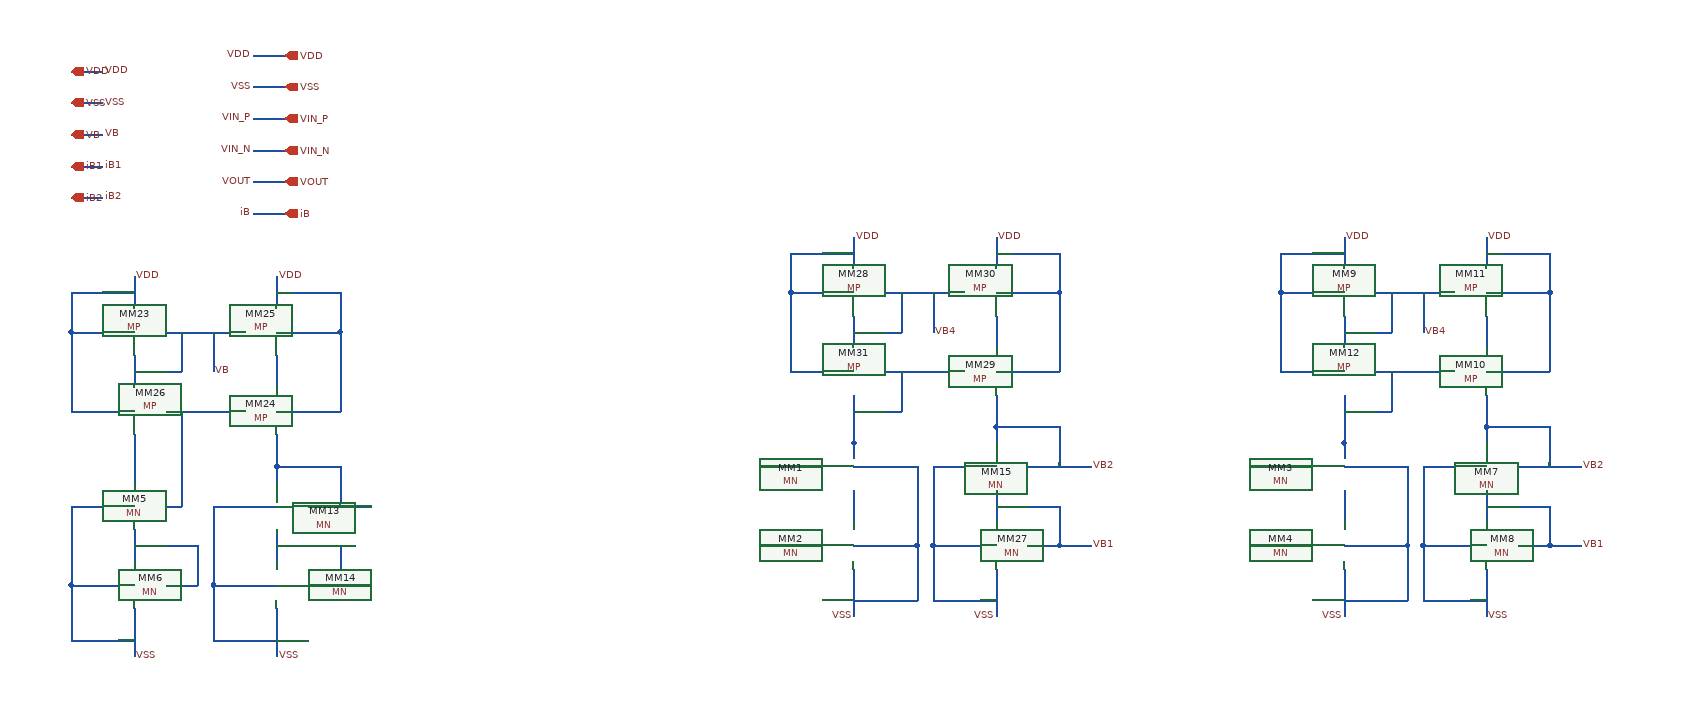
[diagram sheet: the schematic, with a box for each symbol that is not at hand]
v {xschem version=3.4.8RC file_version=1.3}
G {}
K {}
V {}
S {}
F {}
E {}
T {To RF AMP} 160 -520 0 0 0.4 0.4 {}
N -540 -210 -540 -150 {lab=VSS}
N -540 -290 -460 -290 {lab=#net1}
N -500 -240 -460 -240 {lab=#net1}
N -620 -240 -540 -240 {lab=VSS}
N -620 -240 -620 -170 {lab=VSS}
N -620 -170 -540 -170 {lab=VSS}
N -460 -240 -420 -240 {lab=#net1}
N -500 -340 -420 -340 {lab=#net2}
N -460 -290 -460 -240 {lab=#net1}
N -540 -310 -540 -270 {lab=#net1}
N -540 -630 -540 -590 {lab=VDD}
N -540 -560 -460 -560 {lab=VDD}
N -460 -610 -460 -560 {lab=VDD}
N -540 -610 -460 -610 {lab=VDD}
N -540 -530 -540 -490 {lab=#net3}
N -540 -430 -540 -390 {lab=#net2}
N -540 -460 -460 -460 {lab=VDD}
N -460 -560 -460 -460 {lab=VDD}
N -680 -560 -580 -560 {lab=VB}
N -720 -530 -720 -490 {lab=VB}
N -680 -460 -580 -460 {lab=#net4}
N -720 -510 -660 -510 {lab=VB}
N -660 -560 -660 -510 {lab=VB}
N -720 -430 -720 -370 {lab=#net5}
N -720 -630 -720 -590 {lab=VDD}
N -620 -560 -620 -510 {lab=VB}
N -800 -560 -720 -560 {lab=VDD}
N -800 -610 -800 -560 {lab=VDD}
N -800 -610 -720 -610 {lab=VDD}
N -800 -460 -720 -460 {lab=VDD}
N -800 -560 -800 -460 {lab=VDD}
N -540 -390 -540 -370 {lab=#net2}
N -540 -390 -460 -390 {lab=#net2}
N -460 -390 -460 -340 {lab=#net2}
N -620 -340 -540 -340 {lab=VSS}
N -620 -340 -620 -240 {lab=VSS}
N 190 -260 190 -200 {lab=VSS}
N 110 -290 150 -290 {lab=#net6}
N 190 -290 270 -290 {lab=VSS}
N 270 -290 270 -220 {lab=VSS}
N 190 -220 270 -220 {lab=VSS}
N 70 -290 110 -290 {lab=#net6}
N 70 -390 150 -390 {lab=#net7}
N 190 -360 190 -320 {lab=#net8}
N 190 -480 190 -440 {lab=#net9}
N 190 -440 190 -420 {lab=#net9}
N 190 -390 270 -390 {lab=VSS}
N 270 -390 270 -290 {lab=VSS}
N 810 -260 810 -200 {lab=VSS}
N 730 -290 770 -290 {lab=VB1}
N 810 -290 890 -290 {lab=VSS}
N 890 -290 890 -220 {lab=VSS}
N 810 -220 890 -220 {lab=VSS}
N 690 -290 730 -290 {lab=VB1}
N 690 -390 770 -390 {lab=#net10}
N 810 -360 810 -320 {lab=#net11}
N 810 -480 810 -440 {lab=#net12}
N 810 -440 810 -420 {lab=#net12}
N 810 -390 890 -390 {lab=VSS}
N 890 -390 890 -290 {lab=VSS}
N -800 -890 -760 -890 {lab=VDD}
N -800 -850 -760 -850 {lab=VSS}
N -800 -810 -760 -810 {lab=VB}
N -800 -770 -760 -770 {lab=iB1}
N -800 -730 -760 -730 {lab=iB2}
N -720 -210 -720 -150 {lab=VSS}
N -720 -290 -640 -290 {lab=#net13}
N -680 -240 -640 -240 {lab=#net13}
N -800 -240 -720 -240 {lab=VSS}
N -800 -240 -800 -170 {lab=VSS}
N -800 -170 -720 -170 {lab=VSS}
N -640 -290 -640 -240 {lab=#net13}
N -720 -310 -720 -270 {lab=#net13}
N -800 -340 -720 -340 {lab=VSS}
N -800 -340 -800 -240 {lab=VSS}
N -680 -340 -660 -340 {lab=#net4}
N -660 -410 -660 -340 {lab=#net4}
N -660 -460 -660 -410 {lab=#net4}
N 370 -260 370 -200 {lab=VSS}
N 370 -340 450 -340 {lab=VB1}
N 410 -290 450 -290 {lab=VB1}
N 290 -290 370 -290 {lab=VSS}
N 290 -290 290 -220 {lab=VSS}
N 290 -220 370 -220 {lab=VSS}
N 450 -290 490 -290 {lab=VB1}
N 410 -390 490 -390 {lab=VB2}
N 450 -340 450 -290 {lab=VB1}
N 370 -360 370 -320 {lab=VB1}
N 370 -680 370 -640 {lab=VDD}
N 370 -610 450 -610 {lab=VDD}
N 450 -660 450 -610 {lab=VDD}
N 370 -660 450 -660 {lab=VDD}
N 370 -580 370 -540 {lab=#net14}
N 370 -480 370 -440 {lab=VB2}
N 370 -510 450 -510 {lab=VDD}
N 450 -610 450 -510 {lab=VDD}
N 230 -610 330 -610 {lab=VB4}
N 190 -580 190 -540 {lab=VB4}
N 230 -510 330 -510 {lab=#net9}
N 190 -560 250 -560 {lab=VB4}
N 250 -610 250 -560 {lab=VB4}
N 190 -480 190 -420 {lab=#net9}
N 190 -460 250 -460 {lab=#net9}
N 250 -510 250 -460 {lab=#net9}
N 190 -680 190 -640 {lab=VDD}
N 290 -610 290 -560 {lab=VB4}
N -570 -910 -530 -910 {lab=VDD}
N -570 -870 -530 -870 {lab=VSS}
N -570 -830 -530 -830 {lab=VIN_P}
N -570 -790 -530 -790 {lab=VIN_N}
N -570 -750 -530 -750 {lab=VOUT}
N 110 -610 190 -610 {lab=VDD}
N 110 -660 110 -610 {lab=VDD}
N 110 -660 190 -660 {lab=VDD}
N 110 -510 190 -510 {lab=VDD}
N 110 -610 110 -510 {lab=VDD}
N 190 -420 190 -400 {lab=#net9}
N 370 -440 370 -420 {lab=VB2}
N 370 -440 450 -440 {lab=VB2}
N 450 -440 450 -390 {lab=VB2}
N 290 -390 370 -390 {lab=VSS}
N 290 -390 290 -290 {lab=VSS}
N -570 -710 -530 -710 {lab=iB}
N 990 -260 990 -200 {lab=VSS}
N 990 -340 1070 -340 {lab=VB1}
N 1030 -290 1070 -290 {lab=VB1}
N 910 -290 990 -290 {lab=VSS}
N 910 -290 910 -220 {lab=VSS}
N 910 -220 990 -220 {lab=VSS}
N 1070 -290 1110 -290 {lab=VB1}
N 1030 -390 1110 -390 {lab=VB2}
N 1070 -340 1070 -290 {lab=VB1}
N 990 -360 990 -320 {lab=VB1}
N 990 -680 990 -640 {lab=VDD}
N 990 -610 1070 -610 {lab=VDD}
N 1070 -660 1070 -610 {lab=VDD}
N 990 -660 1070 -660 {lab=VDD}
N 990 -580 990 -540 {lab=#net15}
N 990 -480 990 -440 {lab=VB2}
N 990 -510 1070 -510 {lab=VDD}
N 1070 -610 1070 -510 {lab=VDD}
N 850 -610 950 -610 {lab=VB4}
N 810 -580 810 -540 {lab=VB4}
N 850 -510 950 -510 {lab=#net12}
N 810 -560 870 -560 {lab=VB4}
N 870 -610 870 -560 {lab=VB4}
N 810 -480 810 -420 {lab=#net12}
N 810 -460 870 -460 {lab=#net12}
N 870 -510 870 -460 {lab=#net12}
N 810 -680 810 -640 {lab=VDD}
N 910 -610 910 -560 {lab=VB4}
N 730 -610 810 -610 {lab=VDD}
N 730 -660 730 -610 {lab=VDD}
N 730 -660 810 -660 {lab=VDD}
N 730 -510 810 -510 {lab=VDD}
N 730 -610 730 -510 {lab=VDD}
N 810 -420 810 -400 {lab=#net12}
N 990 -440 990 -420 {lab=VB2}
N 990 -440 1070 -440 {lab=VB2}
N 1070 -440 1070 -390 {lab=VB2}
N 910 -390 990 -390 {lab=VSS}
N 910 -390 910 -290 {lab=VSS}
C {MN.sym} -500 -340 0 1 {name=MM13 model=NMOS w=84u l=8u m=1 as=0 ad=0 ps=0 pd=0 nrd=0 nrs=0}
C {MN.sym} -500 -240 0 1 {name=MM14 model=NMOS w=84u l=8u m=1 as=0 ad=0 ps=0 pd=0 nrd=0 nrs=0}
C {devices/lab_pin.sym} -540 -150 0 1 {name=p18 sig_type=std_logic lab=VSS}
C {devices/lab_pin.sym} -540 -630 0 1 {name=p30 sig_type=std_logic lab=VDD}
C {MP.sym} -680 -560 0 1 {name=MM23 model=PMOS w=240u l=8u m=1 as=0 ad=0 ps=0 pd=0 nrd=0 nrs=0}
C {MP.sym} -580 -460 0 0 {name=MM24 model=PMOS w=240u l=8u m=1 as=0 ad=0 ps=0 pd=0 nrd=0 nrs=0}
C {MP.sym} -580 -560 0 0 {name=MM25 model=PMOS w=240u l=8u m=1 as=0 ad=0 ps=0 pd=0 nrd=0 nrs=0}
C {MP.sym} -680 -460 0 1 {name=MM26 model=PMOS w=240u l=8u m=1 as=0 ad=0 ps=0 pd=0 nrd=0 nrs=0}
C {devices/lab_pin.sym} -720 -630 0 1 {name=p34 sig_type=std_logic lab=VDD}
C {devices/lab_pin.sym} -620 -510 0 1 {name=p40 sig_type=std_logic lab=VB}
C {MN.sym} 150 -390 0 0 {name=MM1 model=NMOS w=84u l=8u m=1 as=0 ad=0 ps=0 pd=0 nrd=0 nrs=0}
C {MN.sym} 150 -290 0 0 {name=MM2 model=NMOS w=84u l=8u m=1 as=0 ad=0 ps=0 pd=0 nrd=0 nrs=0}
C {devices/lab_pin.sym} 190 -200 0 0 {name=p1 sig_type=std_logic lab=VSS}
C {MN.sym} 770 -390 0 0 {name=MM3 model=NMOS w=84u l=8u m=1 as=0 ad=0 ps=0 pd=0 nrd=0 nrs=0}
C {MN.sym} 770 -290 0 0 {name=MM4 model=NMOS w=84u l=8u m=1 as=0 ad=0 ps=0 pd=0 nrd=0 nrs=0}
C {devices/lab_pin.sym} 810 -200 0 0 {name=p4 sig_type=std_logic lab=VSS}
C {devices/lab_pin.sym} -760 -730 0 1 {name=p10 sig_type=std_logic lab=iB2}
C {devices/lab_pin.sym} -760 -890 0 1 {name=p11 sig_type=std_logic lab=VDD}
C {devices/lab_pin.sym} -760 -850 0 1 {name=p12 sig_type=std_logic lab=VSS}
C {devices/lab_pin.sym} -760 -810 0 1 {name=p13 sig_type=std_logic lab=VB}
C {devices/lab_pin.sym} -760 -770 0 1 {name=p14 sig_type=std_logic lab=iB1}
C {devices/iopin.sym} -800 -890 0 1 {name=p15 lab=VDD}
C {devices/iopin.sym} -800 -850 0 1 {name=p16 lab=VSS}
C {devices/iopin.sym} -800 -810 0 1 {name=p17 lab=VB}
C {devices/iopin.sym} -800 -770 0 1 {name=p19 lab=iB1}
C {devices/iopin.sym} -800 -730 0 1 {name=p20 lab=iB2}
C {MN.sym} -680 -340 0 1 {name=MM5 model=NMOS w=84u l=8u m=1 as=0 ad=0 ps=0 pd=0 nrd=0 nrs=0}
C {MN.sym} -680 -240 0 1 {name=MM6 model=NMOS w=84u l=8u m=1 as=0 ad=0 ps=0 pd=0 nrd=0 nrs=0}
C {devices/lab_pin.sym} -720 -150 0 1 {name=p5 sig_type=std_logic lab=VSS}
C {devices/opin.sym} -530 -750 0 0 {name=p8 lab=VOUT}
C {devices/ipin.sym} -530 -790 0 1 {name=p25 lab=VIN_N}
C {devices/ipin.sym} -530 -830 0 1 {name=p26 lab=VIN_P}
C {MN.sym} 410 -390 0 1 {name=MM15 model=NMOS w=84u l=8u m=1 as=0 ad=0 ps=0 pd=0 nrd=0 nrs=0}
C {MN.sym} 410 -290 0 1 {name=MM27 model=NMOS w=84u l=8u m=1 as=0 ad=0 ps=0 pd=0 nrd=0 nrs=0}
C {devices/lab_pin.sym} 370 -680 0 1 {name=p44 sig_type=std_logic lab=VDD}
C {devices/lab_pin.sym} 490 -290 0 1 {name=p45 sig_type=std_logic lab=VB1}
C {devices/lab_pin.sym} 490 -390 0 1 {name=p46 sig_type=std_logic lab=VB2}
C {MP.sym} 230 -610 0 1 {name=MM28 model=PMOS w=240u l=8u m=1 as=0 ad=0 ps=0 pd=0 nrd=0 nrs=0}
C {MP.sym} 330 -510 0 0 {name=MM29 model=PMOS w=240u l=8u m=1 as=0 ad=0 ps=0 pd=0 nrd=0 nrs=0}
C {MP.sym} 330 -610 0 0 {name=MM30 model=PMOS w=240u l=8u m=1 as=0 ad=0 ps=0 pd=0 nrd=0 nrs=0}
C {MP.sym} 230 -510 0 1 {name=MM31 model=PMOS w=240u l=8u m=1 as=0 ad=0 ps=0 pd=0 nrd=0 nrs=0}
C {devices/lab_pin.sym} 190 -680 0 1 {name=p47 sig_type=std_logic lab=VDD}
C {devices/ipin.sym} -530 -870 0 1 {name=p51 lab=VSS}
C {devices/ipin.sym} -530 -910 0 1 {name=p52 lab=VDD}
C {devices/lab_pin.sym} 290 -560 0 1 {name=p53 sig_type=std_logic lab=VB4}
C {devices/lab_pin.sym} -570 -910 0 0 {name=p54 sig_type=std_logic lab=VDD}
C {devices/lab_pin.sym} -570 -870 0 0 {name=p55 sig_type=std_logic lab=VSS}
C {devices/lab_pin.sym} -570 -830 0 0 {name=p56 sig_type=std_logic lab=VIN_P}
C {devices/lab_pin.sym} -570 -790 0 0 {name=p57 sig_type=std_logic lab=VIN_N}
C {devices/lab_pin.sym} -570 -750 0 0 {name=p58 sig_type=std_logic lab=VOUT}
C {devices/ipin.sym} -530 -710 0 1 {name=p66 lab=iB}
C {devices/lab_pin.sym} -570 -710 0 0 {name=p67 sig_type=std_logic lab=iB}
C {MN.sym} 1030 -390 0 1 {name=MM7 model=NMOS w=84u l=8u m=1 as=0 ad=0 ps=0 pd=0 nrd=0 nrs=0}
C {MN.sym} 1030 -290 0 1 {name=MM8 model=NMOS w=84u l=8u m=1 as=0 ad=0 ps=0 pd=0 nrd=0 nrs=0}
C {devices/lab_pin.sym} 990 -200 0 1 {name=p22 sig_type=std_logic lab=VSS}
C {devices/lab_pin.sym} 990 -680 0 1 {name=p23 sig_type=std_logic lab=VDD}
C {devices/lab_pin.sym} 1110 -290 0 1 {name=p24 sig_type=std_logic lab=VB1}
C {devices/lab_pin.sym} 1110 -390 0 1 {name=p27 sig_type=std_logic lab=VB2}
C {MP.sym} 850 -610 0 1 {name=MM9 model=PMOS w=240u l=8u m=1 as=0 ad=0 ps=0 pd=0 nrd=0 nrs=0}
C {MP.sym} 950 -510 0 0 {name=MM10 model=PMOS w=240u l=8u m=1 as=0 ad=0 ps=0 pd=0 nrd=0 nrs=0}
C {MP.sym} 950 -610 0 0 {name=MM11 model=PMOS w=240u l=8u m=1 as=0 ad=0 ps=0 pd=0 nrd=0 nrs=0}
C {MP.sym} 850 -510 0 1 {name=MM12 model=PMOS w=240u l=8u m=1 as=0 ad=0 ps=0 pd=0 nrd=0 nrs=0}
C {devices/lab_pin.sym} 810 -680 0 1 {name=p28 sig_type=std_logic lab=VDD}
C {devices/lab_pin.sym} 910 -560 0 1 {name=p29 sig_type=std_logic lab=VB4}
C {devices/lab_pin.sym} 370 -200 0 0 {name=p36 sig_type=std_logic lab=VSS}
